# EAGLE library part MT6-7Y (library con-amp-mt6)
AMP MT6 CONNECTOR

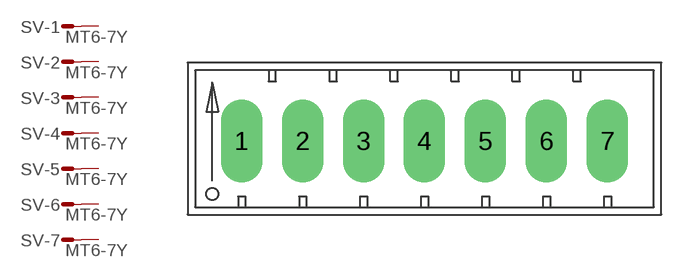
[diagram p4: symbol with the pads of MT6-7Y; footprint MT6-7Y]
Designator prefix SV; gates -1=M -2=M -3=M -4=M -5=M -6=M -7=M

## MT6-7Y (OC_FARNELL: unknown; OC_NEWARK: unknown)  [MT6-7Y]
1  -1:S  pas
2  -2:S  pas
3  -3:S  pas
4  -4:S  pas
5  -5:S  pas
6  -6:S  pas
7  -7:S  pas

## Footprint MT6-7Y (pad centres in mm)
AMP MT6 CONNECTOR
drill 1.803 long: 1 2.54,0; 2 6.502,0; 3 10.465,0; 4 14.427,0; 5 18.39,0; 6 22.352,0; 7 26.314,0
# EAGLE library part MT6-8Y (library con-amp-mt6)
AMP MT6 CONNECTOR

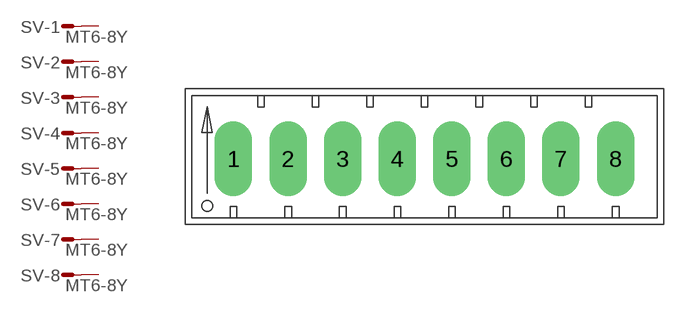
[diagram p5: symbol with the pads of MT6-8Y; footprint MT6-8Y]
Designator prefix SV; gates -1=M -2=M -3=M -4=M -5=M -6=M -7=M -8=M

## MT6-8Y (OC_FARNELL: unknown; OC_NEWARK: unknown)  [MT6-8Y]
1  -1:S  pas
2  -2:S  pas
3  -3:S  pas
4  -4:S  pas
5  -5:S  pas
6  -6:S  pas
7  -7:S  pas
8  -8:S  pas

## Footprint MT6-8Y (pad centres in mm)
AMP MT6 CONNECTOR
drill 1.803 long: 1 2.54,0; 2 6.502,0; 3 10.465,0; 4 14.427,0; 5 18.39,0; 6 22.352,0; 7 26.314,0; 8 30.277,0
